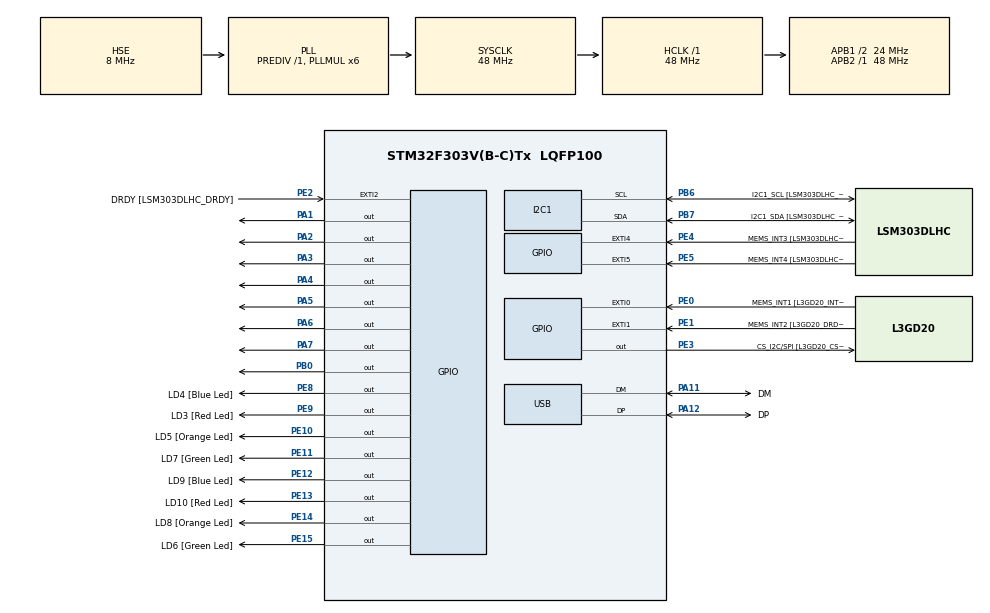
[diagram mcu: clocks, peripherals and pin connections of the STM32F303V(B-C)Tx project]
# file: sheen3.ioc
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I2C1.Timing=0x2000090E
I2C1.Timing-I2C=0x2000090E
Mcu.Family=STM32F3
Mcu.Name=STM32F303V(B-C)Tx
Mcu.Package=LQFP100
NVIC.PriorityGroup=NVIC_PRIORITYGROUP_0
PA1.Signal=GPIO_Output
PA11.GPIO_Label=DM
PA11.Mode=Device
PA11.Signal=USB_DM
PA12.GPIO_Label=DP
PA12.Mode=Device
PA12.Signal=USB_DP
PA13.GPIO_Label=SWDIO
PA13.Mode=Serial_Wire
PA13.Signal=SYS_JTMS-SWDIO
PA14.GPIO_Label=SWCLK
PA14.Mode=Serial_Wire
PA14.Signal=SYS_JTCK-SWCLK
PA2.Signal=GPIO_Output
PA3.Signal=GPIO_Output
PA4.Signal=GPIO_Output
PA5.Signal=GPIO_Output
PA6.Signal=GPIO_Output
PA7.Signal=GPIO_Output
PB0.Signal=GPIO_Output
PB3.GPIO_Label=SWO
PB3.Signal=SYS_JTDO-TRACESWO
PB6.GPIO_Label=I2C1_SCL [LSM303DLHC_SCL]
PB6.GPIO_Pu=GPIO_PULLUP
PB6.Mode=I2C
PB6.Signal=I2C1_SCL
PB7.GPIO_Label=I2C1_SDA [LSM303DLHC_SDA]
PB7.GPIO_Pu=GPIO_PULLUP
PB7.Mode=I2C
PB7.Signal=I2C1_SDA
PC14-OSC32_IN.GPIO_Label=OSC32_IN
PC14-OSC32_IN.Signal=RCC_OSC32_IN
PC15-OSC32_OUT.GPIO_Label=OSC32_OUT
PC15-OSC32_OUT.Signal=RCC_OSC32_OUT
PE0.GPIO_Label=MEMS_INT1 [L3GD20_INT1]
PE0.GPIO_ModeDefaultEXTI=GPIO_MODE_EVT_RISING
PE0.Signal=GPXTI0
PE1.GPIO_Label=MEMS_INT2 [L3GD20_DRDY/INT2]
PE1.GPIO_ModeDefaultEXTI=GPIO_MODE_EVT_RISING
PE1.Signal=GPXTI1
PE10.GPIO_Label=LD5 [Orange Led]
PE10.Signal=GPIO_Output
PE11.GPIO_Label=LD7 [Green Led]
PE11.Signal=GPIO_Output
PE12.GPIO_Label=LD9 [Blue Led]
PE12.Signal=GPIO_Output
PE13.GPIO_Label=LD10 [Red Led]
PE13.Signal=GPIO_Output
PE14.GPIO_Label=LD8 [Orange Led]
PE14.Signal=GPIO_Output
PE15.GPIO_Label=LD6 [Green Led]
PE15.Signal=GPIO_Output
PE2.GPIO_Label=DRDY [LSM303DLHC_DRDY]
PE2.GPIO_ModeDefaultEXTI=GPIO_MODE_EVT_RISING
PE2.Signal=GPXTI2
PE3.GPIO_Label=CS_I2C/SPI [L3GD20_CS_I2C/SPI]
PE3.Signal=GPIO_Output
PE4.GPIO_Label=MEMS_INT3 [LSM303DLHC_INT1]
PE4.GPIO_ModeDefaultEXTI=GPIO_MODE_EVT_RISING
PE4.Signal=GPXTI4
PE5.GPIO_Label=MEMS_INT4 [LSM303DLHC_INT2]
PE5.GPIO_ModeDefaultEXTI=GPIO_MODE_EVT_RISING
PE5.Signal=GPXTI5
PE8.GPIO_Label=LD4 [Blue Led]
PE8.Signal=GPIO_Output
PE9.GPIO_Label=LD3 [Red Led]
PE9.Signal=GPIO_Output
PF0-OSC_IN.GPIO_Label=OSC_IN
PF0-OSC_IN.Mode=HSE-External-Clock-Source
PF0-OSC_IN.Signal=RCC_OSC_IN
PF1-OSC_OUT.GPIO_Label=OSC_OUT
PF1-OSC_OUT.Signal=RCC_OSC_OUT
ProjectManager.HeapSize=0x200
ProjectManager.StackSize=0x400
ProjectManager.TargetToolchain=CMake
RCC.AHBFreq_Value=48000000
RCC.APB1CLKDivider=RCC_HCLK_DIV2
RCC.APB1Freq_Value=24000000
RCC.APB1TimFreq_Value=48000000
RCC.APB2Freq_Value=48000000
RCC.APB2TimFreq_Value=48000000
RCC.CortexFreq_Value=48000000
RCC.HCLKFreq_Value=48000000
RCC.HSE_VALUE=8000000
RCC.HSI_VALUE=8000000
RCC.LSE_VALUE=32768
RCC.PLLMUL=RCC_PLL_MUL6
RCC.SYSCLKFreq_VALUE=48000000
RCC.SYSCLKSourceVirtual=RCC_SYSCLKSOURCE_PLLCLK
RCC.USBFreq_Value=48000000
board=STM32F3DISCOVERY

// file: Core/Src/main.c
/* USER CODE BEGIN Header */
/**
  ******************************************************************************
  * @file           : main.c
  * @brief          : Main program body
  ******************************************************************************
  * @attention
  * Copyright (c) 2025 STMicroelectronics.
  * All rights reserved.
  * This software is licensed under terms that can be found in the LICENSE file
  * in the root directory of this software component.
  * If no LICENSE file comes with this software, it is provided AS-IS.
  ******************************************************************************
  */
/* USER CODE END Header */
#include "main.h"

I2C_HandleTypeDef hi2c1;
PCD_HandleTypeDef hpcd_USB_FS;

void SystemClock_Config(void);
static void MX_GPIO_Init(void);
static void MX_I2C1_Init(void);
static void MX_USB_PCD_Init(void);

/* USER CODE BEGIN 0 */

#define SEG_PORT_A GPIOA
#define SEG_PORT_B GPIOB

static const uint8_t HEX_TO_SEG[16] = {
  0x40,0x79,0x24,0x30,
  0x19,0x12,0x02,0x78,
  0x00,0x10,0x08,0x03,
  0x46,0x21,0x06,0x0E
};

#define COUNTER_BASE 10

typedef struct {
  uint8_t  last_read;
  uint8_t  state;
  uint32_t last_change;
} Debounce;

static inline uint8_t read_btn(GPIO_TypeDef* port, uint16_t pin) {

  return (HAL_GPIO_ReadPin(port, pin) == GPIO_PIN_SET);
}

static uint8_t debounce_update(Debounce* d, uint8_t reading, uint32_t now, uint32_t thr_ms) {
  uint8_t edge = 0;
  if (reading != d->last_read) d->last_change = now;
  if ((now - d->last_change) > thr_ms) {
    if (reading != d->state) {
      d->state = reading;
      if (d->state) edge = 1;   // pressed
    }
  }
  d->last_read = reading;
  return edge;
}

static inline void seg_write_raw(uint8_t segs_7bit, uint8_t dp_on)
{

  uint8_t out = (segs_7bit & 0x7F) | ((dp_on ? 0U : 1U) << 7);

  HAL_GPIO_WritePin(SEG_PORT_B, GPIO_PIN_0, (out & (1 << 0)) ? GPIO_PIN_SET : GPIO_PIN_RESET); // a
  HAL_GPIO_WritePin(SEG_PORT_A, GPIO_PIN_2, (out & (1 << 1)) ? GPIO_PIN_SET : GPIO_PIN_RESET); // b
  HAL_GPIO_WritePin(SEG_PORT_A, GPIO_PIN_5, (out & (1 << 2)) ? GPIO_PIN_SET : GPIO_PIN_RESET); // c
  HAL_GPIO_WritePin(SEG_PORT_A, GPIO_PIN_1, (out & (1 << 3)) ? GPIO_PIN_SET : GPIO_PIN_RESET); // d
  HAL_GPIO_WritePin(SEG_PORT_A, GPIO_PIN_3, (out & (1 << 4)) ? GPIO_PIN_SET : GPIO_PIN_RESET); // e
  HAL_GPIO_WritePin(SEG_PORT_A, GPIO_PIN_4, (out & (1 << 5)) ? GPIO_PIN_SET : GPIO_PIN_RESET); // f
  HAL_GPIO_WritePin(SEG_PORT_A, GPIO_PIN_6, (out & (1 << 6)) ? GPIO_PIN_SET : GPIO_PIN_RESET); // g
  HAL_GPIO_WritePin(SEG_PORT_A, GPIO_PIN_7, (out & (1 << 7)) ? GPIO_PIN_SET : GPIO_PIN_RESET); // dp
}

static inline void display_digit(uint8_t d) {
  seg_write_raw(HEX_TO_SEG[d % 16], 0);
}

/* USER CODE END 0 */

int main(void)
{
  HAL_Init();
  SystemClock_Config();
  MX_GPIO_Init();
  MX_I2C1_Init();
  MX_USB_PCD_Init();

  /* USER CODE BEGIN 2 */
  uint8_t val = 0;
  display_digit(val);

  Debounce inc = {0,0,0};
  Debounce dec = {0,0,0};
  const uint32_t DEBOUNCE_MS = 30;
  /* USER CODE END 2 */

  while (1)
  {
    /* USER CODE BEGIN 3 */
    uint32_t now = HAL_GetTick();

    uint8_t inc_edge = debounce_update(&inc, read_btn(GPIOA, GPIO_PIN_0), now, DEBOUNCE_MS);
    uint8_t dec_edge = debounce_update(&dec, read_btn(GPIOB, GPIO_PIN_5), now, DEBOUNCE_MS);

    if (inc_edge) {
      val = (val + 1) % COUNTER_BASE;
      display_digit(val);
    }
    if (dec_edge) {
      val = (val + COUNTER_BASE - 1) % COUNTER_BASE;
      display_digit(val);
    }

    HAL_Delay(1);
    /* USER CODE END 3 */
  }
}

void SystemClock_Config(void)
{
  RCC_OscInitTypeDef RCC_OscInitStruct = {0};
  RCC_ClkInitTypeDef RCC_ClkInitStruct = {0};
  RCC_PeriphCLKInitTypeDef PeriphClkInit = {0};

  RCC_OscInitStruct.OscillatorType = RCC_OSCILLATORTYPE_HSI|RCC_OSCILLATORTYPE_HSE;
  RCC_OscInitStruct.HSEState = RCC_HSE_BYPASS;
  RCC_OscInitStruct.HSEPredivValue = RCC_HSE_PREDIV_DIV1;
  RCC_OscInitStruct.HSIState = RCC_HSI_ON;
  RCC_OscInitStruct.HSICalibrationValue = RCC_HSICALIBRATION_DEFAULT;
  RCC_OscInitStruct.PLL.PLLState = RCC_PLL_ON;
  RCC_OscInitStruct.PLL.PLLSource = RCC_PLLSOURCE_HSE;
  RCC_OscInitStruct.PLL.PLLMUL = RCC_PLL_MUL6;
  if (HAL_RCC_OscConfig(&RCC_OscInitStruct) != HAL_OK) { Error_Handler(); }

  RCC_ClkInitStruct.ClockType = RCC_CLOCKTYPE_HCLK|RCC_CLOCKTYPE_SYSCLK
                              |RCC_CLOCKTYPE_PCLK1|RCC_CLOCKTYPE_PCLK2;
  RCC_ClkInitStruct.SYSCLKSource = RCC_SYSCLKSOURCE_PLLCLK;
  RCC_ClkInitStruct.AHBCLKDivider = RCC_SYSCLK_DIV1;
  RCC_ClkInitStruct.APB1CLKDivider = RCC_HCLK_DIV2;
  RCC_ClkInitStruct.APB2CLKDivider = RCC_HCLK_DIV1;

  if (HAL_RCC_ClockConfig(&RCC_ClkInitStruct, FLASH_LATENCY_1) != HAL_OK) { Error_Handler(); }

  PeriphClkInit.PeriphClockSelection = RCC_PERIPHCLK_USB|RCC_PERIPHCLK_I2C1;
  PeriphClkInit.I2c1ClockSelection = RCC_I2C1CLKSOURCE_HSI;
  PeriphClkInit.USBClockSelection = RCC_USBCLKSOURCE_PLL;
  if (HAL_RCCEx_PeriphCLKConfig(&PeriphClkInit) != HAL_OK) { Error_Handler(); }
}

static void MX_I2C1_Init(void)
{
  hi2c1.Instance = I2C1;
  hi2c1.Init.Timing = 0x2000090E;
  hi2c1.Init.OwnAddress1 = 0;
  hi2c1.Init.AddressingMode = I2C_ADDRESSINGMODE_7BIT;
  hi2c1.Init.DualAddressMode = I2C_DUALADDRESS_DISABLE;
  hi2c1.Init.OwnAddress2 = 0;
  hi2c1.Init.OwnAddress2Masks = I2C_OA2_NOMASK;
  hi2c1.Init.GeneralCallMode = I2C_GENERALCALL_DISABLE;
  hi2c1.Init.NoStretchMode = I2C_NOSTRETCH_DISABLE;
  if (HAL_I2C_Init(&hi2c1) != HAL_OK) { Error_Handler(); }
  if (HAL_I2CEx_ConfigAnalogFilter(&hi2c1, I2C_ANALOGFILTER_ENABLE) != HAL_OK) { Error_Handler(); }
  if (HAL_I2CEx_ConfigDigitalFilter(&hi2c1, 0) != HAL_OK) { Error_Handler(); }
}

static void MX_USB_PCD_Init(void)
{
  hpcd_USB_FS.Instance = USB;
  hpcd_USB_FS.Init.dev_endpoints = 8;
  hpcd_USB_FS.Init.speed = PCD_SPEED_FULL;
  hpcd_USB_FS.Init.phy_itface = PCD_PHY_EMBEDDED;
  hpcd_USB_FS.Init.low_power_enable = DISABLE;
  hpcd_USB_FS.Init.battery_charging_enable = DISABLE;
  if (HAL_PCD_Init(&hpcd_USB_FS) != HAL_OK) { Error_Handler(); }
}

static void MX_GPIO_Init(void)
{
  GPIO_InitTypeDef GPIO_InitStruct = {0};

  /* GPIO Ports Clock Enable */
  __HAL_RCC_GPIOE_CLK_ENABLE();
  __HAL_RCC_GPIOC_CLK_ENABLE();
  __HAL_RCC_GPIOF_CLK_ENABLE();
  __HAL_RCC_GPIOA_CLK_ENABLE();
  __HAL_RCC_GPIOB_CLK_ENABLE();

  HAL_GPIO_WritePin(GPIOE, CS_I2C_SPI_Pin|LD4_Pin|LD3_Pin|LD5_Pin
                          |LD7_Pin|LD9_Pin|LD10_Pin|LD8_Pin
                          |LD6_Pin, GPIO_PIN_RESET);
  GPIO_InitStruct.Pin = CS_I2C_SPI_Pin|LD4_Pin|LD3_Pin|LD5_Pin
                          |LD7_Pin|LD9_Pin|LD10_Pin|LD8_Pin
                          |LD6_Pin;
  GPIO_InitStruct.Mode = GPIO_MODE_OUTPUT_PP;
  GPIO_InitStruct.Pull = GPIO_NOPULL;
  GPIO_InitStruct.Speed = GPIO_SPEED_FREQ_LOW;
  HAL_GPIO_Init(GPIOE, &GPIO_InitStruct);

  HAL_GPIO_WritePin(GPIOA, GPIO_PIN_1|GPIO_PIN_2|GPIO_PIN_3|
                            GPIO_PIN_4|GPIO_PIN_5|GPIO_PIN_6|GPIO_PIN_7, GPIO_PIN_SET);
  HAL_GPIO_WritePin(GPIOB, GPIO_PIN_0, GPIO_PIN_SET); // 'a' OFF

  GPIO_InitStruct.Pin = GPIO_PIN_0;
  GPIO_InitStruct.Mode = GPIO_MODE_INPUT;
  GPIO_InitStruct.Pull = GPIO_PULLDOWN;
  HAL_GPIO_Init(GPIOA, &GPIO_InitStruct);

  // PB5 external button as input with pulldown (active-HIGH when pressed)
  GPIO_InitStruct.Pin = GPIO_PIN_5;
  GPIO_InitStruct.Mode = GPIO_MODE_INPUT;
  GPIO_InitStruct.Pull = GPIO_PULLDOWN;
  HAL_GPIO_Init(GPIOB, &GPIO_InitStruct);

  // PA1..PA7 outputs (b..g, dp)
  GPIO_InitStruct.Pin = GPIO_PIN_1|GPIO_PIN_2|GPIO_PIN_3|
                        GPIO_PIN_4|GPIO_PIN_5|GPIO_PIN_6|GPIO_PIN_7;
  GPIO_InitStruct.Mode = GPIO_MODE_OUTPUT_PP;
  GPIO_InitStruct.Pull = GPIO_NOPULL;
  GPIO_InitStruct.Speed = GPIO_SPEED_FREQ_LOW;
  HAL_GPIO_Init(GPIOA, &GPIO_InitStruct);

  // PB0 output ('a')
  GPIO_InitStruct.Pin = GPIO_PIN_0;
  GPIO_InitStruct.Mode = GPIO_MODE_OUTPUT_PP;
  GPIO_InitStruct.Pull = GPIO_NOPULL;
  GPIO_InitStruct.Speed = GPIO_SPEED_FREQ_LOW;
  HAL_GPIO_Init(GPIOB, &GPIO_InitStruct);
}

void Error_Handler(void)
{
  __disable_irq();
  while (1) { }
}
